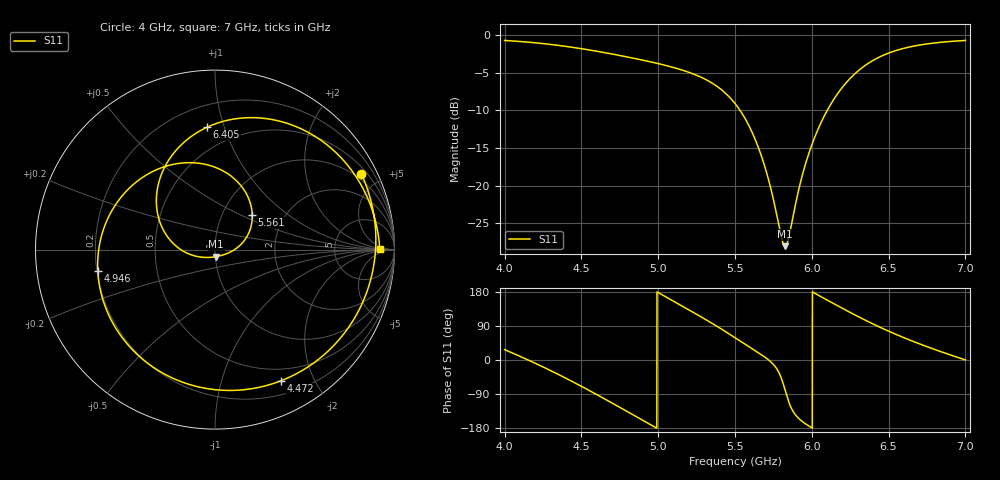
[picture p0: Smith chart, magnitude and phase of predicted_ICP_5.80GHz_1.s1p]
! ICP-predicted S11, target max centred GHz at -10 dB. Complex ensemble mean (passive and causal);
! its |S11| can differ slightly from the dB-domain mean reported in designs.csv.
!  Air_gap = 3.64mm
!  W_Patch = 12.15mm
!  L_Patch = 17.32mm
!  Sx = 1.34mm
!  Sy = 3.48mm
!  W_Patch1 = 10.88mm
!  WS = 0.78mm
!  Curve_Amp1 = 0.97mm
!  Extra = 3.35mm
# GHz S MA R 50
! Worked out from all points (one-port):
!   3001 points, 4 GHz to 7 GHz, reference 50 ohm
!   lowest |S11| = -28.0 dB at 5.826 GHz (marker M1), VSWR 1.08, Z = 50.6 - j3.95 ohm
!   |S11| at or under -10 dB: 5.532 GHz to 6.101 GHz (568.7 MHz wide, 9.78 % of centre)
!   S11 on the Smith chart (normalised r, x): 4 GHz: 0.74, +3.98; 4.472 GHz: 0.35, -1.56; 4.946 GHz: 0.20, -0.09; 5.561 GHz: 1.38, +0.58; 6.405 GHz: 0.34, +0.87; 7 GHz: 23, +1
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4  0.918 27.3
4.19  0.8876 -6.9
4.281  0.8682 -24.3
4.375  0.845 -43.2
4.472  0.8179 -63.4
4.608  0.776 -93.1
4.75  0.7296 -125.0
4.85  0.6963 -147.8
4.946  0.6637 -169.7
5.125  0.5968 149.5
5.221  0.5541 127.4
5.311  0.5046 106.3
5.4  0.4423 84.6
5.5  0.3506 59.1
5.561  0.284 43.1
5.685  0.1432 10.2
5.803  0.04499 -49.5
5.826  0.03969 -79.4
5.875  0.06038 -133.5
5.945  0.1242 -164.4
6.028  0.2206 174.3
6.149  0.3816 147.3
6.25  0.5149 125.4
6.405  0.6828 93.8
6.512  0.765 73.9
6.625  0.8261 54.7
6.814  0.8871 25.8
7  0.9179 0.2
